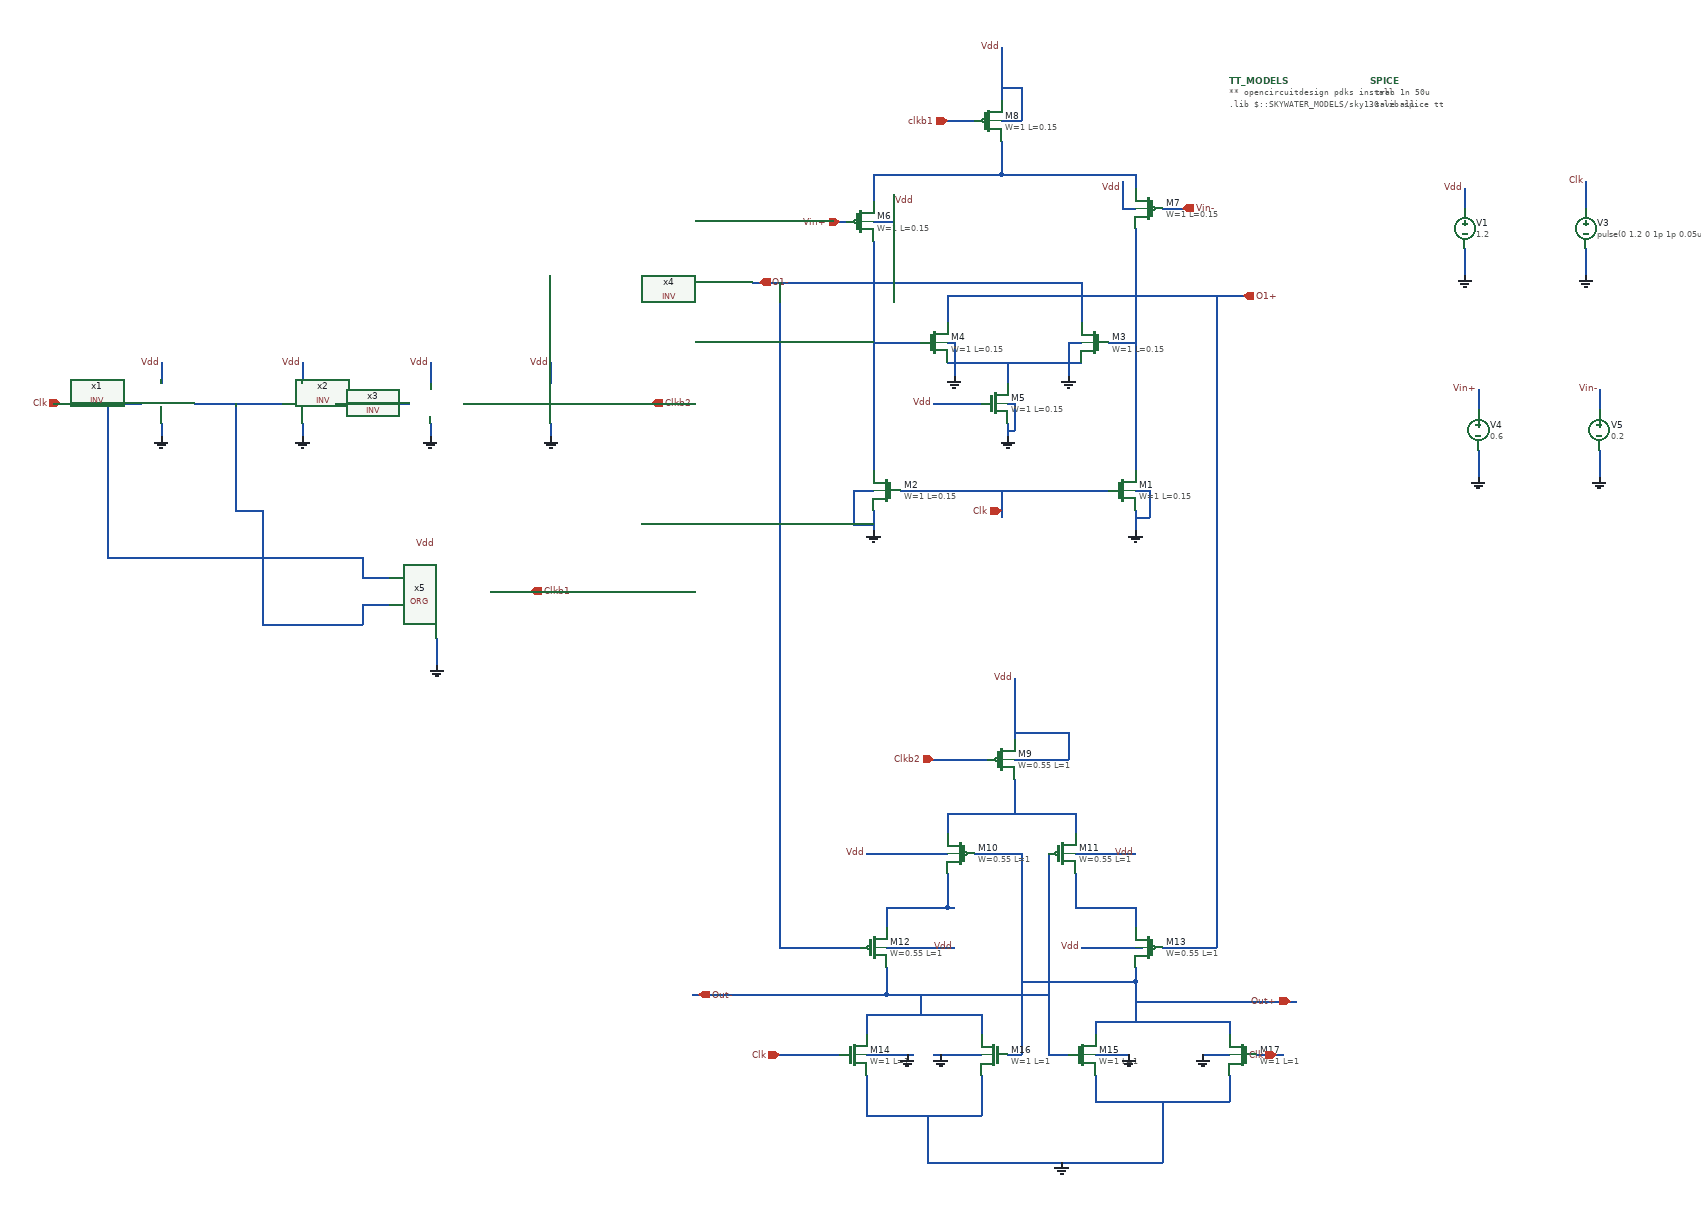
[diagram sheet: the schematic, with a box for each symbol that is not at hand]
v {xschem version=3.0.0 file_version=1.2 }
G {}
K {}
V {}
S {}
E {}
N 2310 -1720 2310 -1670 {
lab=#net1}
N 2310 -1670 2510 -1670 {
lab=#net1}
N 2510 -1670 2510 -1650 {
lab=#net1}
N 2120 -1670 2310 -1670 {
lab=#net1}
N 2120 -1670 2120 -1630 {
lab=#net1}
N 2510 -1590 2510 -1230 {
lab=O1+}
N 2120 -1570 2120 -1230 {
lab=O1-}
N 2160 -1200 2470 -1200 {
lab=clk}
N 2230 -1390 2430 -1390 {
lab=#net2}
N 2320 -1390 2320 -1360 {
lab=#net2}
N 2210 -1330 2280 -1330 {
lab=Vdd}
N 2230 -1490 2230 -1450 {
lab=O1+}
N 2230 -1490 2510 -1490 {
lab=O1+}
N 2430 -1510 2430 -1450 {
lab=O1-}
N 2120 -1510 2430 -1510 {
lab=O1-}
N 2120 -1420 2190 -1420 {
lab=O1-}
N 2470 -1420 2510 -1420 {
lab=O1+}
N 2310 -1860 2310 -1780 {
lab=Vdd}
N 2220 -1750 2270 -1750 {
lab=clkb1}
N 2120 -1170 2120 -1140 {
lab=GND}
N 2510 -1170 2510 -1140 {
lab=GND}
N 2320 -1300 2320 -1280 {
lab=GND}
N 2060 -1600 2080 -1600 {
lab=Vin+}
N 2550 -1620 2590 -1620 {
lab=Vin-}
N 2510 -1490 2680 -1490 {
lab=O1+}
N 1940 -1510 2120 -1510 {
lab=O1-}
N 3000 -1650 3000 -1620 {
lab=Vdd}
N 3000 -1560 3000 -1520 {
lab=GND}
N 3180 -1560 3180 -1520 {
lab=GND}
N 3180 -1660 3180 -1620 {
lab=Clk}
N 2310 -1200 2310 -1160 {
lab=clk}
N 3020 -1350 3020 -1320 {
lab=Vin+}
N 3020 -1260 3020 -1220 {
lab=GND}
N 3200 -1350 3200 -1320 {
lab=Vin-}
N 3200 -1260 3200 -1220 {
lab=GND}
N 2310 -1800 2340 -1800 {
lab=Vdd}
N 2340 -1800 2340 -1750 {
lab=Vdd}
N 2310 -1750 2340 -1750 {
lab=Vdd}
N 2150 -1640 2150 -1600 {
lab=Vdd}
N 2120 -1600 2150 -1600 {
lab=Vdd}
N 2490 -1660 2490 -1620 {
lab=Vdd}
N 2490 -1620 2510 -1620 {
lab=Vdd}
N 2230 -1420 2240 -1420 {
lab=GND}
N 2410 -1420 2430 -1420 {
lab=GND}
N 2320 -1290 2330 -1290 {
lab=GND}
N 2330 -1330 2330 -1290 {
lab=GND}
N 2320 -1330 2330 -1330 {
lab=GND}
N 2090 -1200 2120 -1200 {
lab=GND}
N 2090 -1200 2090 -1150 {
lab=GND}
N 2090 -1150 2120 -1150 {
lab=GND}
N 2510 -1200 2530 -1200 {
lab=GND}
N 2530 -1200 2530 -1160 {
lab=GND}
N 2510 -1160 2530 -1160 {
lab=GND}
N 2240 -1420 2240 -1370 {
lab=GND}
N 2410 -1420 2410 -1370 {
lab=GND}
N 1110 -1330 1240 -1330 {
lab=#net3}
N 1320 -1330 1430 -1330 {
lab=#net4}
N 1510 -1330 1610 -1330 {
lab=#net5}
N 1060 -1390 1060 -1360 {
lab=Vdd}
N 1270 -1390 1270 -1360 {
lab=Vdd}
N 1460 -1390 1460 -1360 {
lab=Vdd}
N 1640 -1390 1640 -1360 {
lab=Vdd}
N 900 -1330 1030 -1330 {
lab=Clk}
N 980 -1330 980 -1130 {
lab=Clk}
N 1170 -1330 1170 -1170 {
lab=#net3}
N 1690 -1330 1790 -1330 {
lab=Clkb2}
N 1060 -1300 1060 -1280 {
lab=GND}
N 1270 -1300 1270 -1280 {
lab=GND}
N 1460 -1300 1460 -1280 {
lab=GND}
N 1640 -1300 1640 -1280 {
lab=GND}
N 2330 -770 2330 -720 {
lab=#net6}
N 2230 -720 2230 -690 {
lab=#net6}
N 2420 -720 2420 -690 {
lab=#net6}
N 2230 -630 2230 -620 {
lab=#net7}
N 2230 -630 2230 -580 {
lab=#net7}
N 2140 -580 2230 -580 {
lab=#net7}
N 2140 -580 2140 -550 {
lab=#net7}
N 2510 -580 2510 -550 {
lab=#net8}
N 2420 -580 2510 -580 {
lab=#net8}
N 2420 -630 2420 -580 {
lab=#net8}
N 2380 -660 2380 -360 {
lab=Out-}
N 2380 -360 2410 -360 {
lab=Out-}
N 2320 -360 2340 -360 {
lab=Out+}
N 2340 -660 2340 -360 {
lab=Out+}
N 2270 -660 2340 -660 {
lab=Out+}
N 2510 -490 2510 -470 {
lab=Out+}
N 2340 -470 2510 -470 {
lab=Out+}
N 2140 -490 2140 -450 {
lab=Out-}
N 2140 -450 2380 -450 {
lab=Out-}
N 2280 -420 2280 -390 {
lab=Out-}
N 2110 -420 2280 -420 {
lab=Out-}
N 2110 -420 2110 -390 {
lab=Out-}
N 2650 -410 2650 -390 {
lab=Out+}
N 2450 -410 2650 -410 {
lab=Out+}
N 2450 -410 2450 -390 {
lab=Out+}
N 2650 -330 2650 -290 {
lab=GND}
N 2450 -290 2650 -290 {
lab=GND}
N 2450 -330 2450 -290 {
lab=GND}
N 2280 -330 2280 -270 {
lab=GND}
N 2110 -330 2110 -270 {
lab=GND}
N 2210 -360 2280 -360 {
lab=GND}
N 2110 -360 2180 -360 {
lab=GND}
N 2550 -290 2550 -200 {
lab=GND}
N 2200 -200 2550 -200 {
lab=GND}
N 2200 -270 2200 -200 {
lab=GND}
N 2550 -520 2630 -520 {
lab=O1+}
N 2060 -520 2100 -520 {
lab=O1-}
N 2690 -360 2730 -360 {
lab=Clk}
N 1970 -360 2070 -360 {
lab=Clk}
N 2420 -660 2510 -660 {
lab=Vdd}
N 2110 -660 2230 -660 {
lab=Vdd}
N 2510 -470 2510 -410 {
lab=Out+}
N 2190 -450 2190 -420 {
lab=Out-}
N 2140 -520 2240 -520 {
lab=Vdd}
N 2230 -580 2240 -580 {
lab=#net7}
N 2430 -520 2520 -520 {
lab=Vdd}
N 2450 -360 2500 -360 {
lab=GND}
N 2610 -360 2650 -360 {
lab=GND}
N 2330 -800 2410 -800 {
lab=Vdd}
N 2410 -840 2410 -800 {
lab=Vdd}
N 2390 -840 2410 -840 {
lab=Vdd}
N 2330 -840 2390 -840 {
lab=Vdd}
N 2330 -840 2330 -830 {
lab=Vdd}
N 2330 -920 2330 -830 {
lab=Vdd}
N 2210 -800 2290 -800 {
lab=Clkb2}
N 2200 -800 2210 -800 {
lab=Clkb2}
N 1850 -450 2140 -450 {
lab=Out-}
N 2510 -440 2750 -440 {
lab=Out+}
N 2230 -720 2420 -720 {
lab=#net6}
N 1980 -1510 1980 -520 {
lab=O1-}
N 1980 -520 2060 -520 {
lab=O1-}
N 2630 -1490 2630 -750 {
lab=O1+}
N 2630 -750 2630 -520 {
lab=O1+}
N 2110 -270 2280 -270 {
lab=GND}
N 1220 -1000 1310 -1000 {
lab=#net3}
N 1170 -1170 1210 -1170 {
lab=#net3}
N 1210 -1170 1210 -1000 {
lab=#net3}
N 1210 -1000 1220 -1000 {
lab=#net3}
N 980 -1130 980 -1100 {
lab=Clk}
N 980 -1100 1100 -1100 {
lab=Clk}
N 1360 -1070 1400 -1070 {
lab=Clk}
N 1310 -1000 1360 -1000 {
lab=#net3}
N 1360 -1030 1360 -1000 {
lab=#net3}
N 1360 -1030 1400 -1030 {
lab=#net3}
N 1470 -980 1470 -940 {
lab=GND}
N 1550 -1050 1610 -1050 {
lab=Clkb1}
N 1100 -1100 1360 -1100 {
lab=Clk}
N 1360 -1100 1360 -1070 {
lab=Clk}
C {sky130_fd_pr/nfet_01v8.sym} 2490 -1200 0 0 {name=M1
L=0.15
W=1
nf=1 
mult=1
ad="'int((nf+1)/2) * W/nf * 0.29'" 
pd="'2*int((nf+1)/2) * (W/nf + 0.29)'"
as="'int((nf+2)/2) * W/nf * 0.29'" 
ps="'2*int((nf+2)/2) * (W/nf + 0.29)'"
nrd="'0.29 / W'" nrs="'0.29 / W'"
sa=0 sb=0 sd=0
model=nfet_01v8
spiceprefix=X
}
C {sky130_fd_pr/nfet_01v8.sym} 2140 -1200 0 1 {name=M2
L=0.15
W=1
nf=1 
mult=1
ad="'int((nf+1)/2) * W/nf * 0.29'" 
pd="'2*int((nf+1)/2) * (W/nf + 0.29)'"
as="'int((nf+2)/2) * W/nf * 0.29'" 
ps="'2*int((nf+2)/2) * (W/nf + 0.29)'"
nrd="'0.29 / W'" nrs="'0.29 / W'"
sa=0 sb=0 sd=0
model=nfet_01v8
spiceprefix=X
}
C {sky130_fd_pr/nfet_01v8.sym} 2450 -1420 0 1 {name=M3
L=0.15
W=1
nf=1 
mult=1
ad="'int((nf+1)/2) * W/nf * 0.29'" 
pd="'2*int((nf+1)/2) * (W/nf + 0.29)'"
as="'int((nf+2)/2) * W/nf * 0.29'" 
ps="'2*int((nf+2)/2) * (W/nf + 0.29)'"
nrd="'0.29 / W'" nrs="'0.29 / W'"
sa=0 sb=0 sd=0
model=nfet_01v8
spiceprefix=X
}
C {sky130_fd_pr/nfet_01v8.sym} 2210 -1420 0 0 {name=M4
L=0.15
W=1
nf=1 
mult=1
ad="'int((nf+1)/2) * W/nf * 0.29'" 
pd="'2*int((nf+1)/2) * (W/nf + 0.29)'"
as="'int((nf+2)/2) * W/nf * 0.29'" 
ps="'2*int((nf+2)/2) * (W/nf + 0.29)'"
nrd="'0.29 / W'" nrs="'0.29 / W'"
sa=0 sb=0 sd=0
model=nfet_01v8
spiceprefix=X
}
C {sky130_fd_pr/nfet_01v8.sym} 2300 -1330 0 0 {name=M5
L=0.15
W=1
nf=1 
mult=1
ad="'int((nf+1)/2) * W/nf * 0.29'" 
pd="'2*int((nf+1)/2) * (W/nf + 0.29)'"
as="'int((nf+2)/2) * W/nf * 0.29'" 
ps="'2*int((nf+2)/2) * (W/nf + 0.29)'"
nrd="'0.29 / W'" nrs="'0.29 / W'"
sa=0 sb=0 sd=0
model=nfet_01v8
spiceprefix=X
}
C {sky130_fd_pr/pfet_01v8.sym} 2100 -1600 0 0 {name=M6
L=0.15
W=1
nf=1
mult=1
ad="'int((nf+1)/2) * W/nf * 0.29'" 
pd="'2*int((nf+1)/2) * (W/nf + 0.29)'"
as="'int((nf+2)/2) * W/nf * 0.29'" 
ps="'2*int((nf+2)/2) * (W/nf + 0.29)'"
nrd="'0.29 / W'" nrs="'0.29 / W'"
sa=0 sb=0 sd=0
model=pfet_01v8
spiceprefix=X
}
C {sky130_fd_pr/pfet_01v8.sym} 2530 -1620 0 1 {name=M7
L=0.15
W=1
nf=1
mult=1
ad="'int((nf+1)/2) * W/nf * 0.29'" 
pd="'2*int((nf+1)/2) * (W/nf + 0.29)'"
as="'int((nf+2)/2) * W/nf * 0.29'" 
ps="'2*int((nf+2)/2) * (W/nf + 0.29)'"
nrd="'0.29 / W'" nrs="'0.29 / W'"
sa=0 sb=0 sd=0
model=pfet_01v8
spiceprefix=X
}
C {sky130_fd_pr/pfet_01v8.sym} 2290 -1750 0 0 {name=M8
L=0.15
W=1
nf=1
mult=1
ad="'int((nf+1)/2) * W/nf * 0.29'" 
pd="'2*int((nf+1)/2) * (W/nf + 0.29)'"
as="'int((nf+2)/2) * W/nf * 0.29'" 
ps="'2*int((nf+2)/2) * (W/nf + 0.29)'"
nrd="'0.29 / W'" nrs="'0.29 / W'"
sa=0 sb=0 sd=0
model=pfet_01v8
spiceprefix=X
}
C {devices/code.sym} 2650 -1810 0 0 {name=TT_MODELS
only_toplevel=true
format="tcleval( @value )"
value="
** opencircuitdesign pdks install
.lib $::SKYWATER_MODELS/sky130.lib.spice tt

"
spice_ignore=false}
C {devices/gnd.sym} 2120 -1140 0 0 {name=l1 lab=GND}
C {devices/gnd.sym} 2510 -1140 0 0 {name=l2 lab=GND}
C {devices/gnd.sym} 2320 -1280 0 0 {name=l3 lab=GND}
C {devices/ipin.sym} 2230 -1750 0 0 {name=p1 lab=clkb1}
C {devices/ipin.sym} 2070 -1600 0 0 {name=p2 lab=Vin+}
C {devices/ipin.sym} 2580 -1620 0 1 {name=p3 lab=Vin-}
C {devices/opin.sym} 2670 -1490 0 0 {name=p6 lab=O1+}
C {devices/opin.sym} 1950 -1510 2 0 {name=p7 lab=O1-}
C {devices/lab_pin.sym} 2310 -1860 0 0 {name=l4 sig_type=std_logic lab=Vdd}
C {devices/lab_pin.sym} 2210 -1330 0 0 {name=l5 sig_type=std_logic lab=Vdd}
C {devices/code_shown.sym} 2860 -1810 0 0 {name=SPICE only_toplevel=false value=".tran 1n 50u
.save all"}
C {devices/vsource.sym} 3000 -1590 0 0 {name=V1 value=1.2}
C {devices/lab_pin.sym} 3000 -1650 1 0 {name=l6 sig_type=std_logic lab=Vdd}
C {devices/gnd.sym} 3000 -1520 0 0 {name=l7 lab=GND}
C {devices/vsource.sym} 3180 -1590 0 0 {name=V3 value="pulse(0 1.2 0 1p 1p 0.05u 0.1u)"}
C {devices/gnd.sym} 3180 -1520 0 0 {name=l10 lab=GND}
C {devices/lab_pin.sym} 3180 -1660 1 0 {name=l11 sig_type=std_logic lab=Clk}
C {devices/ipin.sym} 2310 -1170 3 0 {name=p4 lab=Clk}
C {devices/vsource.sym} 3020 -1290 0 0 {name=V4 value=0.6}
C {devices/lab_pin.sym} 3020 -1350 1 0 {name=l12 sig_type=std_logic lab=Vin+}
C {devices/gnd.sym} 3020 -1220 0 0 {name=l13 lab=GND}
C {devices/vsource.sym} 3200 -1290 0 0 {name=V5 value=0.2}
C {devices/lab_pin.sym} 3200 -1350 1 0 {name=l14 sig_type=std_logic lab=Vin-}
C {devices/gnd.sym} 3200 -1220 0 0 {name=l15 lab=GND}
C {devices/gnd.sym} 2240 -1370 0 0 {name=l16 lab=GND}
C {devices/gnd.sym} 2410 -1370 0 0 {name=l17 lab=GND}
C {devices/lab_pin.sym} 2490 -1650 0 0 {name=l18 sig_type=std_logic lab=Vdd}
C {devices/lab_pin.sym} 2150 -1630 2 0 {name=l19 sig_type=std_logic lab=Vdd}
C {devices/lab_pin.sym} 1060 -1390 1 0 {name=l20 sig_type=std_logic lab=Vdd}
C {devices/lab_pin.sym} 1270 -1390 1 0 {name=l21 sig_type=std_logic lab=Vdd}
C {devices/lab_pin.sym} 1460 -1390 1 0 {name=l31 sig_type=std_logic lab=Vdd}
C {devices/lab_pin.sym} 1640 -1390 1 0 {name=l34 sig_type=std_logic lab=Vdd}
C {devices/gnd.sym} 1060 -1280 0 0 {name=l36 lab=GND}
C {devices/gnd.sym} 1270 -1280 0 0 {name=l37 lab=GND}
C {devices/gnd.sym} 1460 -1280 0 0 {name=l38 lab=GND}
C {devices/gnd.sym} 1640 -1280 0 0 {name=l39 lab=GND}
C {devices/ipin.sym} 910 -1330 0 0 {name=p12 lab=Clk}
C {devices/opin.sym} 1790 -1330 0 0 {name=p13 lab=Clkb2}
C {sky130_fd_pr/pfet_01v8.sym} 2310 -800 0 0 {name=M9
L=1
W=0.55
ad="'W * 0.29'" pd="'W + 2 * 0.29'"
as="'W * 0.29'" ps="'W + 2 * 0.29'"
nrd=0 nrs=0
sa=0 sb=0 sd=0
nf=1 mult=1
model=pfet_01v8
spiceprefix=X
 }
C {sky130_fd_pr/pfet_01v8.sym} 2250 -660 0 1 {name=M10
L=1
W=0.55
ad="'W * 0.29'" pd="'W + 2 * 0.29'"
as="'W * 0.29'" ps="'W + 2 * 0.29'"
nrd=0 nrs=0
sa=0 sb=0 sd=0
nf=1 mult=1
model=pfet_01v8
spiceprefix=X
 }
C {sky130_fd_pr/pfet_01v8.sym} 2400 -660 0 0 {name=M11
L=1
W=0.55
ad="'W * 0.29'" pd="'W + 2 * 0.29'"
as="'W * 0.29'" ps="'W + 2 * 0.29'"
nrd=0 nrs=0
sa=0 sb=0 sd=0
nf=1 mult=1
model=pfet_01v8
spiceprefix=X
 }
C {sky130_fd_pr/pfet_01v8.sym} 2120 -520 0 0 {name=M12
L=1
W=0.55
ad="'W * 0.29'" pd="'W + 2 * 0.29'"
as="'W * 0.29'" ps="'W + 2 * 0.29'"
nrd=0 nrs=0
sa=0 sb=0 sd=0
nf=1 mult=1
model=pfet_01v8
spiceprefix=X
 }
C {sky130_fd_pr/pfet_01v8.sym} 2530 -520 0 1 {name=M13
L=1
W=0.55
ad="'W * 0.29'" pd="'W + 2 * 0.29'"
as="'W * 0.29'" ps="'W + 2 * 0.29'"
nrd=0 nrs=0
sa=0 sb=0 sd=0
nf=1 mult=1
model=pfet_01v8
spiceprefix=X
 }
C {sky130_fd_pr/nfet_01v8_lvt.sym} 2090 -360 0 0 {name=M14
L=1
W=1
ad="'W * 0.29'" pd="'2*(W + 0.29)'"
as="'W * 0.29'" ps="'2*(W + 0.29)'"
nrd=0 nrs=0
sa=0 sb=0 sd=0
nf=1 mult=1
model=nfet_01v8_lvt
spiceprefix=X
 }
C {sky130_fd_pr/nfet_01v8_lvt.sym} 2430 -360 0 0 {name=M15
L=1
W=1
ad="'W * 0.29'" pd="'2*(W + 0.29)'"
as="'W * 0.29'" ps="'2*(W + 0.29)'"
nrd=0 nrs=0
sa=0 sb=0 sd=0
nf=1 mult=1
model=nfet_01v8_lvt
spiceprefix=X
 }
C {sky130_fd_pr/nfet_01v8_lvt.sym} 2300 -360 0 1 {name=M16
L=1
W=1
ad="'W * 0.29'" pd="'2*(W + 0.29)'"
as="'W * 0.29'" ps="'2*(W + 0.29)'"
nrd=0 nrs=0
sa=0 sb=0 sd=0
nf=1 mult=1
model=nfet_01v8_lvt
spiceprefix=X
 }
C {sky130_fd_pr/nfet_01v8_lvt.sym} 2670 -360 0 1 {name=M17
L=1
W=1
ad="'W * 0.29'" pd="'2*(W + 0.29)'"
as="'W * 0.29'" ps="'2*(W + 0.29)'"
nrd=0 nrs=0
sa=0 sb=0 sd=0
nf=1 mult=1
model=nfet_01v8_lvt
spiceprefix=X
 }
C {devices/lab_pin.sym} 2330 -920 0 0 {name=l22 sig_type=std_logic lab=Vdd
}
C {devices/gnd.sym} 2400 -200 0 0 {name=l23 lab=GND}
C {devices/ipin.sym} 2210 -800 0 0 {name=p8 lab=Clkb2}
C {devices/opin.sym} 2740 -440 2 1 {name=p9 lab=Out+}
C {devices/opin.sym} 1860 -450 2 0 {name=p10 lab=Out-}
C {devices/lab_pin.sym} 2110 -660 1 0 {name=l24 sig_type=std_logic lab=Vdd
}
C {devices/lab_pin.sym} 2510 -660 1 0 {name=l25 sig_type=std_logic lab=Vdd
}
C {devices/lab_pin.sym} 2240 -520 1 0 {name=l26 sig_type=std_logic lab=Vdd
}
C {devices/lab_pin.sym} 2430 -520 1 0 {name=l27 sig_type=std_logic lab=Vdd
}
C {devices/gnd.sym} 2170 -360 0 0 {name=l28 lab=GND}
C {devices/gnd.sym} 2220 -360 0 0 {name=l29 lab=GND}
C {devices/gnd.sym} 2500 -360 0 0 {name=l30 lab=GND}
C {devices/gnd.sym} 2610 -360 0 0 {name=l32 lab=GND}
C {devices/ipin.sym} 1980 -360 0 0 {name=p5 lab=Clk}
C {devices/ipin.sym} 2720 -360 2 0 {name=p11 lab=Clk}
C {devices/opin.sym} 1610 -1050 0 0 {name=p16 lab=Clkb1}
C {devices/lab_pin.sym} 1470 -1120 1 0 {name=l8 sig_type=std_logic lab=Vdd}
C {devices/gnd.sym} 1470 -940 0 0 {name=l9 lab=GND}
C {pico/akshat_comp/ezyzip/PICO/Inverter/INV.sym} 1010 -1330 0 0 {name=x1}
C {pico/akshat_comp/ezyzip/PICO/Inverter/INV.sym} 1220 -1330 0 0 {name=x2}
C {pico/akshat_comp/ezyzip/PICO/Inverter/INV.sym} 1410 -1330 0 0 {name=x3}
C {pico/akshat_comp/ezyzip/PICO/Inverter/INV.sym} 1590 -1330 0 0 {name=x4}
C {pico/akshat_comp/ezyzip/PICO/OR_gate/ORG.sym} 1210 -920 0 0 {name=x5}
